VERSION 5.7 ;
BUSBITCHARS "[]" ;
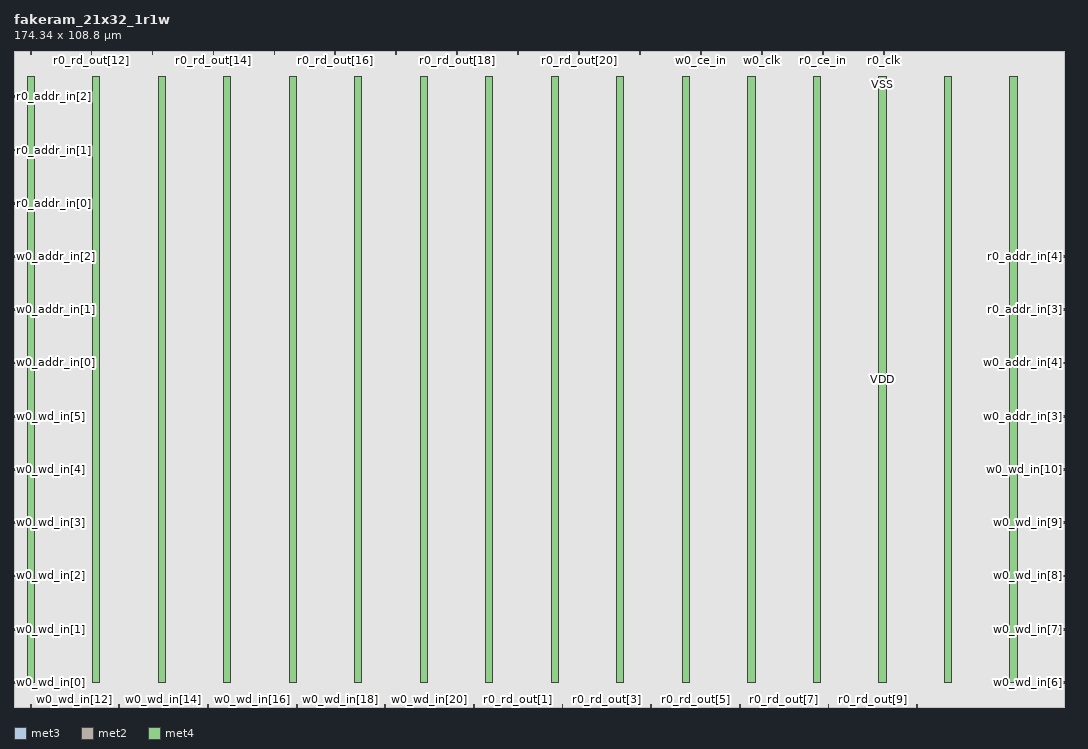
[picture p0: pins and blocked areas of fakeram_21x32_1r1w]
MACRO fakeram_21x32_1r1w
  FOREIGN fakeram_21x32_1r1w 0 0 ;
  SYMMETRY X Y R90 ;
  SIZE 174.340 BY 108.800 ;
  CLASS BLOCK ;
  PIN w0_wd_in[0]
    DIRECTION INPUT ;
    USE SIGNAL ;
    SHAPE ABUTMENT ;
    PORT
      LAYER met3 ;
      RECT 0.000 3.930 0.900 4.230 ;
    END
  END w0_wd_in[0]
  PIN w0_wd_in[1]
    DIRECTION INPUT ;
    USE SIGNAL ;
    SHAPE ABUTMENT ;
    PORT
      LAYER met3 ;
      RECT 0.000 12.770 0.900 13.070 ;
    END
  END w0_wd_in[1]
  PIN w0_wd_in[2]
    DIRECTION INPUT ;
    USE SIGNAL ;
    SHAPE ABUTMENT ;
    PORT
      LAYER met3 ;
      RECT 0.000 21.610 0.900 21.910 ;
    END
  END w0_wd_in[2]
  PIN w0_wd_in[3]
    DIRECTION INPUT ;
    USE SIGNAL ;
    SHAPE ABUTMENT ;
    PORT
      LAYER met3 ;
      RECT 0.000 30.450 0.900 30.750 ;
    END
  END w0_wd_in[3]
  PIN w0_wd_in[4]
    DIRECTION INPUT ;
    USE SIGNAL ;
    SHAPE ABUTMENT ;
    PORT
      LAYER met3 ;
      RECT 0.000 39.290 0.900 39.590 ;
    END
  END w0_wd_in[4]
  PIN w0_wd_in[5]
    DIRECTION INPUT ;
    USE SIGNAL ;
    SHAPE ABUTMENT ;
    PORT
      LAYER met3 ;
      RECT 0.000 48.130 0.900 48.430 ;
    END
  END w0_wd_in[5]
  PIN w0_wd_in[6]
    DIRECTION INPUT ;
    USE SIGNAL ;
    SHAPE ABUTMENT ;
    PORT
      LAYER met3 ;
      RECT 173.440 3.930 174.340 4.230 ;
    END
  END w0_wd_in[6]
  PIN w0_wd_in[7]
    DIRECTION INPUT ;
    USE SIGNAL ;
    SHAPE ABUTMENT ;
    PORT
      LAYER met3 ;
      RECT 173.440 12.770 174.340 13.070 ;
    END
  END w0_wd_in[7]
  PIN w0_wd_in[8]
    DIRECTION INPUT ;
    USE SIGNAL ;
    SHAPE ABUTMENT ;
    PORT
      LAYER met3 ;
      RECT 173.440 21.610 174.340 21.910 ;
    END
  END w0_wd_in[8]
  PIN w0_wd_in[9]
    DIRECTION INPUT ;
    USE SIGNAL ;
    SHAPE ABUTMENT ;
    PORT
      LAYER met3 ;
      RECT 173.440 30.450 174.340 30.750 ;
    END
  END w0_wd_in[9]
  PIN w0_wd_in[10]
    DIRECTION INPUT ;
    USE SIGNAL ;
    SHAPE ABUTMENT ;
    PORT
      LAYER met3 ;
      RECT 173.440 39.290 174.340 39.590 ;
    END
  END w0_wd_in[10]
  PIN w0_wd_in[11]
    DIRECTION INPUT ;
    USE SIGNAL ;
    SHAPE ABUTMENT ;
    PORT
      LAYER met2 ;
      RECT 2.690 0.000 2.830 0.420 ;
    END
  END w0_wd_in[11]
  PIN w0_wd_in[12]
    DIRECTION INPUT ;
    USE SIGNAL ;
    SHAPE ABUTMENT ;
    PORT
      LAYER met2 ;
      RECT 10.050 0.000 10.190 0.420 ;
    END
  END w0_wd_in[12]
  PIN w0_wd_in[13]
    DIRECTION INPUT ;
    USE SIGNAL ;
    SHAPE ABUTMENT ;
    PORT
      LAYER met2 ;
      RECT 17.410 0.000 17.550 0.420 ;
    END
  END w0_wd_in[13]
  PIN w0_wd_in[14]
    DIRECTION INPUT ;
    USE SIGNAL ;
    SHAPE ABUTMENT ;
    PORT
      LAYER met2 ;
      RECT 24.770 0.000 24.910 0.420 ;
    END
  END w0_wd_in[14]
  PIN w0_wd_in[15]
    DIRECTION INPUT ;
    USE SIGNAL ;
    SHAPE ABUTMENT ;
    PORT
      LAYER met2 ;
      RECT 32.130 0.000 32.270 0.420 ;
    END
  END w0_wd_in[15]
  PIN w0_wd_in[16]
    DIRECTION INPUT ;
    USE SIGNAL ;
    SHAPE ABUTMENT ;
    PORT
      LAYER met2 ;
      RECT 39.490 0.000 39.630 0.420 ;
    END
  END w0_wd_in[16]
  PIN w0_wd_in[17]
    DIRECTION INPUT ;
    USE SIGNAL ;
    SHAPE ABUTMENT ;
    PORT
      LAYER met2 ;
      RECT 46.850 0.000 46.990 0.420 ;
    END
  END w0_wd_in[17]
  PIN w0_wd_in[18]
    DIRECTION INPUT ;
    USE SIGNAL ;
    SHAPE ABUTMENT ;
    PORT
      LAYER met2 ;
      RECT 54.210 0.000 54.350 0.420 ;
    END
  END w0_wd_in[18]
  PIN w0_wd_in[19]
    DIRECTION INPUT ;
    USE SIGNAL ;
    SHAPE ABUTMENT ;
    PORT
      LAYER met2 ;
      RECT 61.570 0.000 61.710 0.420 ;
    END
  END w0_wd_in[19]
  PIN w0_wd_in[20]
    DIRECTION INPUT ;
    USE SIGNAL ;
    SHAPE ABUTMENT ;
    PORT
      LAYER met2 ;
      RECT 68.930 0.000 69.070 0.420 ;
    END
  END w0_wd_in[20]
  PIN r0_rd_out[0]
    DIRECTION OUTPUT ;
    USE SIGNAL ;
    SHAPE ABUTMENT ;
    PORT
      LAYER met2 ;
      RECT 76.290 0.000 76.430 0.420 ;
    END
  END r0_rd_out[0]
  PIN r0_rd_out[1]
    DIRECTION OUTPUT ;
    USE SIGNAL ;
    SHAPE ABUTMENT ;
    PORT
      LAYER met2 ;
      RECT 83.650 0.000 83.790 0.420 ;
    END
  END r0_rd_out[1]
  PIN r0_rd_out[2]
    DIRECTION OUTPUT ;
    USE SIGNAL ;
    SHAPE ABUTMENT ;
    PORT
      LAYER met2 ;
      RECT 91.010 0.000 91.150 0.420 ;
    END
  END r0_rd_out[2]
  PIN r0_rd_out[3]
    DIRECTION OUTPUT ;
    USE SIGNAL ;
    SHAPE ABUTMENT ;
    PORT
      LAYER met2 ;
      RECT 98.370 0.000 98.510 0.420 ;
    END
  END r0_rd_out[3]
  PIN r0_rd_out[4]
    DIRECTION OUTPUT ;
    USE SIGNAL ;
    SHAPE ABUTMENT ;
    PORT
      LAYER met2 ;
      RECT 105.730 0.000 105.870 0.420 ;
    END
  END r0_rd_out[4]
  PIN r0_rd_out[5]
    DIRECTION OUTPUT ;
    USE SIGNAL ;
    SHAPE ABUTMENT ;
    PORT
      LAYER met2 ;
      RECT 113.090 0.000 113.230 0.420 ;
    END
  END r0_rd_out[5]
  PIN r0_rd_out[6]
    DIRECTION OUTPUT ;
    USE SIGNAL ;
    SHAPE ABUTMENT ;
    PORT
      LAYER met2 ;
      RECT 120.450 0.000 120.590 0.420 ;
    END
  END r0_rd_out[6]
  PIN r0_rd_out[7]
    DIRECTION OUTPUT ;
    USE SIGNAL ;
    SHAPE ABUTMENT ;
    PORT
      LAYER met2 ;
      RECT 127.810 0.000 127.950 0.420 ;
    END
  END r0_rd_out[7]
  PIN r0_rd_out[8]
    DIRECTION OUTPUT ;
    USE SIGNAL ;
    SHAPE ABUTMENT ;
    PORT
      LAYER met2 ;
      RECT 135.170 0.000 135.310 0.420 ;
    END
  END r0_rd_out[8]
  PIN r0_rd_out[9]
    DIRECTION OUTPUT ;
    USE SIGNAL ;
    SHAPE ABUTMENT ;
    PORT
      LAYER met2 ;
      RECT 142.530 0.000 142.670 0.420 ;
    END
  END r0_rd_out[9]
  PIN r0_rd_out[10]
    DIRECTION OUTPUT ;
    USE SIGNAL ;
    SHAPE ABUTMENT ;
    PORT
      LAYER met2 ;
      RECT 149.890 0.000 150.030 0.420 ;
    END
  END r0_rd_out[10]
  PIN r0_rd_out[11]
    DIRECTION OUTPUT ;
    USE SIGNAL ;
    SHAPE ABUTMENT ;
    PORT
      LAYER met2 ;
      RECT 2.690 108.380 2.830 108.800 ;
    END
  END r0_rd_out[11]
  PIN r0_rd_out[12]
    DIRECTION OUTPUT ;
    USE SIGNAL ;
    SHAPE ABUTMENT ;
    PORT
      LAYER met2 ;
      RECT 12.810 108.380 12.950 108.800 ;
    END
  END r0_rd_out[12]
  PIN r0_rd_out[13]
    DIRECTION OUTPUT ;
    USE SIGNAL ;
    SHAPE ABUTMENT ;
    PORT
      LAYER met2 ;
      RECT 22.930 108.380 23.070 108.800 ;
    END
  END r0_rd_out[13]
  PIN r0_rd_out[14]
    DIRECTION OUTPUT ;
    USE SIGNAL ;
    SHAPE ABUTMENT ;
    PORT
      LAYER met2 ;
      RECT 33.050 108.380 33.190 108.800 ;
    END
  END r0_rd_out[14]
  PIN r0_rd_out[15]
    DIRECTION OUTPUT ;
    USE SIGNAL ;
    SHAPE ABUTMENT ;
    PORT
      LAYER met2 ;
      RECT 43.170 108.380 43.310 108.800 ;
    END
  END r0_rd_out[15]
  PIN r0_rd_out[16]
    DIRECTION OUTPUT ;
    USE SIGNAL ;
    SHAPE ABUTMENT ;
    PORT
      LAYER met2 ;
      RECT 53.290 108.380 53.430 108.800 ;
    END
  END r0_rd_out[16]
  PIN r0_rd_out[17]
    DIRECTION OUTPUT ;
    USE SIGNAL ;
    SHAPE ABUTMENT ;
    PORT
      LAYER met2 ;
      RECT 63.410 108.380 63.550 108.800 ;
    END
  END r0_rd_out[17]
  PIN r0_rd_out[18]
    DIRECTION OUTPUT ;
    USE SIGNAL ;
    SHAPE ABUTMENT ;
    PORT
      LAYER met2 ;
      RECT 73.530 108.380 73.670 108.800 ;
    END
  END r0_rd_out[18]
  PIN r0_rd_out[19]
    DIRECTION OUTPUT ;
    USE SIGNAL ;
    SHAPE ABUTMENT ;
    PORT
      LAYER met2 ;
      RECT 83.650 108.380 83.790 108.800 ;
    END
  END r0_rd_out[19]
  PIN r0_rd_out[20]
    DIRECTION OUTPUT ;
    USE SIGNAL ;
    SHAPE ABUTMENT ;
    PORT
      LAYER met2 ;
      RECT 93.770 108.380 93.910 108.800 ;
    END
  END r0_rd_out[20]
  PIN w0_addr_in[0]
    DIRECTION INPUT ;
    USE SIGNAL ;
    SHAPE ABUTMENT ;
    PORT
      LAYER met3 ;
      RECT 0.000 56.970 0.900 57.270 ;
    END
  END w0_addr_in[0]
  PIN w0_addr_in[1]
    DIRECTION INPUT ;
    USE SIGNAL ;
    SHAPE ABUTMENT ;
    PORT
      LAYER met3 ;
      RECT 0.000 65.810 0.900 66.110 ;
    END
  END w0_addr_in[1]
  PIN w0_addr_in[2]
    DIRECTION INPUT ;
    USE SIGNAL ;
    SHAPE ABUTMENT ;
    PORT
      LAYER met3 ;
      RECT 0.000 74.650 0.900 74.950 ;
    END
  END w0_addr_in[2]
  PIN w0_addr_in[3]
    DIRECTION INPUT ;
    USE SIGNAL ;
    SHAPE ABUTMENT ;
    PORT
      LAYER met3 ;
      RECT 173.440 48.130 174.340 48.430 ;
    END
  END w0_addr_in[3]
  PIN w0_addr_in[4]
    DIRECTION INPUT ;
    USE SIGNAL ;
    SHAPE ABUTMENT ;
    PORT
      LAYER met3 ;
      RECT 173.440 56.970 174.340 57.270 ;
    END
  END w0_addr_in[4]
  PIN r0_addr_in[0]
    DIRECTION INPUT ;
    USE SIGNAL ;
    SHAPE ABUTMENT ;
    PORT
      LAYER met3 ;
      RECT 0.000 83.490 0.900 83.790 ;
    END
  END r0_addr_in[0]
  PIN r0_addr_in[1]
    DIRECTION INPUT ;
    USE SIGNAL ;
    SHAPE ABUTMENT ;
    PORT
      LAYER met3 ;
      RECT 0.000 92.330 0.900 92.630 ;
    END
  END r0_addr_in[1]
  PIN r0_addr_in[2]
    DIRECTION INPUT ;
    USE SIGNAL ;
    SHAPE ABUTMENT ;
    PORT
      LAYER met3 ;
      RECT 0.000 101.170 0.900 101.470 ;
    END
  END r0_addr_in[2]
  PIN r0_addr_in[3]
    DIRECTION INPUT ;
    USE SIGNAL ;
    SHAPE ABUTMENT ;
    PORT
      LAYER met3 ;
      RECT 173.440 65.810 174.340 66.110 ;
    END
  END r0_addr_in[3]
  PIN r0_addr_in[4]
    DIRECTION INPUT ;
    USE SIGNAL ;
    SHAPE ABUTMENT ;
    PORT
      LAYER met3 ;
      RECT 173.440 74.650 174.340 74.950 ;
    END
  END r0_addr_in[4]
  PIN w0_we_in
    DIRECTION INPUT ;
    USE SIGNAL ;
    SHAPE ABUTMENT ;
    PORT
      LAYER met2 ;
      RECT 103.890 108.380 104.030 108.800 ;
    END
  END w0_we_in
  PIN w0_ce_in
    DIRECTION INPUT ;
    USE SIGNAL ;
    SHAPE ABUTMENT ;
    PORT
      LAYER met2 ;
      RECT 114.010 108.380 114.150 108.800 ;
    END
  END w0_ce_in
  PIN w0_clk
    DIRECTION INPUT ;
    USE SIGNAL ;
    SHAPE ABUTMENT ;
    PORT
      LAYER met2 ;
      RECT 124.130 108.380 124.270 108.800 ;
    END
  END w0_clk
  PIN r0_ce_in
    DIRECTION INPUT ;
    USE SIGNAL ;
    SHAPE ABUTMENT ;
    PORT
      LAYER met2 ;
      RECT 134.250 108.380 134.390 108.800 ;
    END
  END r0_ce_in
  PIN r0_clk
    DIRECTION INPUT ;
    USE SIGNAL ;
    SHAPE ABUTMENT ;
    PORT
      LAYER met2 ;
      RECT 144.370 108.380 144.510 108.800 ;
    END
  END r0_clk
  PIN VSS
    DIRECTION INOUT ;
    USE GROUND ;
    PORT
      LAYER met4 ;
      RECT 2.160 4.080 3.360 104.720 ;
      RECT 13.040 4.080 14.240 104.720 ;
      RECT 23.920 4.080 25.120 104.720 ;
      RECT 34.800 4.080 36.000 104.720 ;
      RECT 45.680 4.080 46.880 104.720 ;
      RECT 56.560 4.080 57.760 104.720 ;
      RECT 67.440 4.080 68.640 104.720 ;
      RECT 78.320 4.080 79.520 104.720 ;
      RECT 89.200 4.080 90.400 104.720 ;
      RECT 100.080 4.080 101.280 104.720 ;
      RECT 110.960 4.080 112.160 104.720 ;
      RECT 121.840 4.080 123.040 104.720 ;
      RECT 132.720 4.080 133.920 104.720 ;
      RECT 143.600 4.080 144.800 104.720 ;
      RECT 154.480 4.080 155.680 104.720 ;
      RECT 165.360 4.080 166.560 104.720 ;
    END
  END VSS
  PIN VDD
    DIRECTION INOUT ;
    USE POWER ;
    PORT
      LAYER met4 ;
      RECT 2.160 4.080 3.360 104.720 ;
      RECT 13.040 4.080 14.240 104.720 ;
      RECT 23.920 4.080 25.120 104.720 ;
      RECT 34.800 4.080 36.000 104.720 ;
      RECT 45.680 4.080 46.880 104.720 ;
      RECT 56.560 4.080 57.760 104.720 ;
      RECT 67.440 4.080 68.640 104.720 ;
      RECT 78.320 4.080 79.520 104.720 ;
      RECT 89.200 4.080 90.400 104.720 ;
      RECT 100.080 4.080 101.280 104.720 ;
      RECT 110.960 4.080 112.160 104.720 ;
      RECT 121.840 4.080 123.040 104.720 ;
      RECT 132.720 4.080 133.920 104.720 ;
      RECT 143.600 4.080 144.800 104.720 ;
      RECT 154.480 4.080 155.680 104.720 ;
      RECT 165.360 4.080 166.560 104.720 ;
    END
  END VDD
  OBS
    LAYER met1 ;
    RECT 0 0 174.340 108.800 ;
    LAYER met2 ;
    RECT 0 0 174.340 108.800 ;
    LAYER met3 ;
    RECT 0 0 174.340 108.800 ;
    LAYER met4 ;
    RECT 0 0 174.340 108.800 ;
  END
END fakeram_21x32_1r1w

END LIBRARY
